VERSION 5.7 ;
BUSBITCHARS "[]" ;
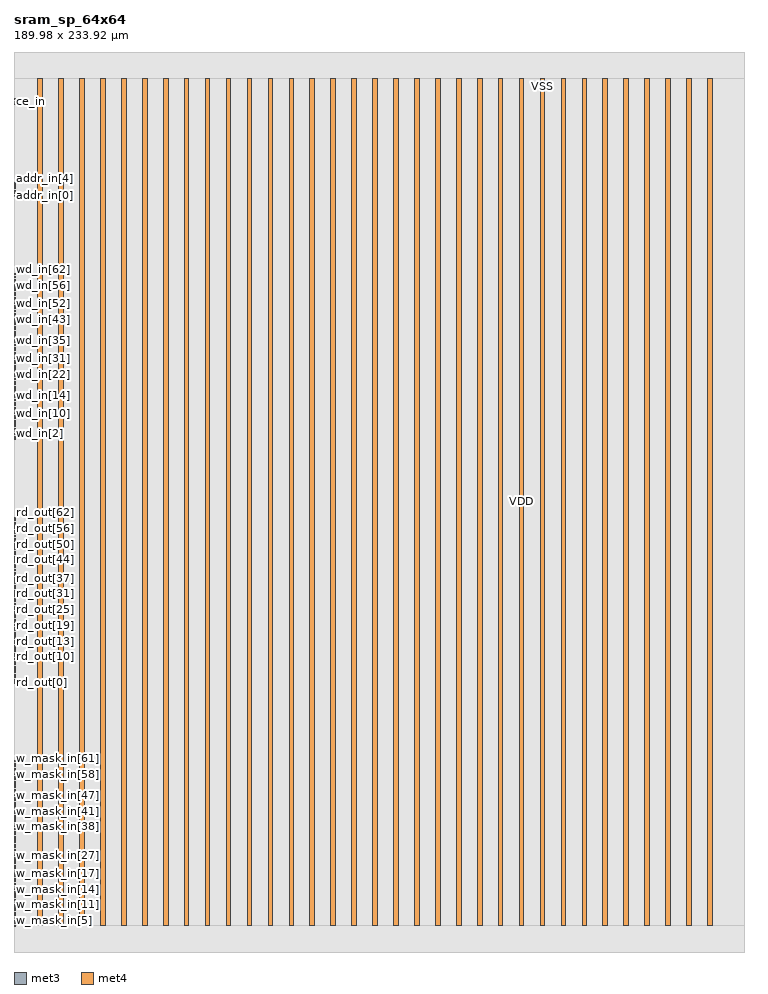
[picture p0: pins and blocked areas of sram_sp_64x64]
MACRO sram_sp_64x64
  FOREIGN sram_sp_64x64 0 0 ;
  SYMMETRY X Y R90 ;
  SIZE 189.980 BY 233.920 ;
  CLASS BLOCK ;
  PIN w_mask_in[0]
    DIRECTION INPUT ;
    USE SIGNAL ;
    SHAPE ABUTMENT ;
    PORT
      LAYER met3 ;
      RECT 0.000 6.650 0.300 6.950 ;
    END
  END w_mask_in[0]
  PIN w_mask_in[1]
    DIRECTION INPUT ;
    USE SIGNAL ;
    SHAPE ABUTMENT ;
    PORT
      LAYER met3 ;
      RECT 0.000 7.330 0.300 7.630 ;
    END
  END w_mask_in[1]
  PIN w_mask_in[2]
    DIRECTION INPUT ;
    USE SIGNAL ;
    SHAPE ABUTMENT ;
    PORT
      LAYER met3 ;
      RECT 0.000 8.010 0.300 8.310 ;
    END
  END w_mask_in[2]
  PIN w_mask_in[3]
    DIRECTION INPUT ;
    USE SIGNAL ;
    SHAPE ABUTMENT ;
    PORT
      LAYER met3 ;
      RECT 0.000 8.690 0.300 8.990 ;
    END
  END w_mask_in[3]
  PIN w_mask_in[4]
    DIRECTION INPUT ;
    USE SIGNAL ;
    SHAPE ABUTMENT ;
    PORT
      LAYER met3 ;
      RECT 0.000 9.370 0.300 9.670 ;
    END
  END w_mask_in[4]
  PIN w_mask_in[5]
    DIRECTION INPUT ;
    USE SIGNAL ;
    SHAPE ABUTMENT ;
    PORT
      LAYER met3 ;
      RECT 0.000 10.050 0.300 10.350 ;
    END
  END w_mask_in[5]
  PIN w_mask_in[6]
    DIRECTION INPUT ;
    USE SIGNAL ;
    SHAPE ABUTMENT ;
    PORT
      LAYER met3 ;
      RECT 0.000 10.730 0.300 11.030 ;
    END
  END w_mask_in[6]
  PIN w_mask_in[7]
    DIRECTION INPUT ;
    USE SIGNAL ;
    SHAPE ABUTMENT ;
    PORT
      LAYER met3 ;
      RECT 0.000 11.410 0.300 11.710 ;
    END
  END w_mask_in[7]
  PIN w_mask_in[8]
    DIRECTION INPUT ;
    USE SIGNAL ;
    SHAPE ABUTMENT ;
    PORT
      LAYER met3 ;
      RECT 0.000 12.090 0.300 12.390 ;
    END
  END w_mask_in[8]
  PIN w_mask_in[9]
    DIRECTION INPUT ;
    USE SIGNAL ;
    SHAPE ABUTMENT ;
    PORT
      LAYER met3 ;
      RECT 0.000 12.770 0.300 13.070 ;
    END
  END w_mask_in[9]
  PIN w_mask_in[10]
    DIRECTION INPUT ;
    USE SIGNAL ;
    SHAPE ABUTMENT ;
    PORT
      LAYER met3 ;
      RECT 0.000 13.450 0.300 13.750 ;
    END
  END w_mask_in[10]
  PIN w_mask_in[11]
    DIRECTION INPUT ;
    USE SIGNAL ;
    SHAPE ABUTMENT ;
    PORT
      LAYER met3 ;
      RECT 0.000 14.130 0.300 14.430 ;
    END
  END w_mask_in[11]
  PIN w_mask_in[12]
    DIRECTION INPUT ;
    USE SIGNAL ;
    SHAPE ABUTMENT ;
    PORT
      LAYER met3 ;
      RECT 0.000 14.810 0.300 15.110 ;
    END
  END w_mask_in[12]
  PIN w_mask_in[13]
    DIRECTION INPUT ;
    USE SIGNAL ;
    SHAPE ABUTMENT ;
    PORT
      LAYER met3 ;
      RECT 0.000 15.490 0.300 15.790 ;
    END
  END w_mask_in[13]
  PIN w_mask_in[14]
    DIRECTION INPUT ;
    USE SIGNAL ;
    SHAPE ABUTMENT ;
    PORT
      LAYER met3 ;
      RECT 0.000 16.170 0.300 16.470 ;
    END
  END w_mask_in[14]
  PIN w_mask_in[15]
    DIRECTION INPUT ;
    USE SIGNAL ;
    SHAPE ABUTMENT ;
    PORT
      LAYER met3 ;
      RECT 0.000 16.850 0.300 17.150 ;
    END
  END w_mask_in[15]
  PIN w_mask_in[16]
    DIRECTION INPUT ;
    USE SIGNAL ;
    SHAPE ABUTMENT ;
    PORT
      LAYER met3 ;
      RECT 0.000 17.530 0.300 17.830 ;
    END
  END w_mask_in[16]
  PIN w_mask_in[17]
    DIRECTION INPUT ;
    USE SIGNAL ;
    SHAPE ABUTMENT ;
    PORT
      LAYER met3 ;
      RECT 0.000 18.210 0.300 18.510 ;
    END
  END w_mask_in[17]
  PIN w_mask_in[18]
    DIRECTION INPUT ;
    USE SIGNAL ;
    SHAPE ABUTMENT ;
    PORT
      LAYER met3 ;
      RECT 0.000 18.890 0.300 19.190 ;
    END
  END w_mask_in[18]
  PIN w_mask_in[19]
    DIRECTION INPUT ;
    USE SIGNAL ;
    SHAPE ABUTMENT ;
    PORT
      LAYER met3 ;
      RECT 0.000 19.570 0.300 19.870 ;
    END
  END w_mask_in[19]
  PIN w_mask_in[20]
    DIRECTION INPUT ;
    USE SIGNAL ;
    SHAPE ABUTMENT ;
    PORT
      LAYER met3 ;
      RECT 0.000 20.250 0.300 20.550 ;
    END
  END w_mask_in[20]
  PIN w_mask_in[21]
    DIRECTION INPUT ;
    USE SIGNAL ;
    SHAPE ABUTMENT ;
    PORT
      LAYER met3 ;
      RECT 0.000 20.930 0.300 21.230 ;
    END
  END w_mask_in[21]
  PIN w_mask_in[22]
    DIRECTION INPUT ;
    USE SIGNAL ;
    SHAPE ABUTMENT ;
    PORT
      LAYER met3 ;
      RECT 0.000 21.610 0.300 21.910 ;
    END
  END w_mask_in[22]
  PIN w_mask_in[23]
    DIRECTION INPUT ;
    USE SIGNAL ;
    SHAPE ABUTMENT ;
    PORT
      LAYER met3 ;
      RECT 0.000 22.290 0.300 22.590 ;
    END
  END w_mask_in[23]
  PIN w_mask_in[24]
    DIRECTION INPUT ;
    USE SIGNAL ;
    SHAPE ABUTMENT ;
    PORT
      LAYER met3 ;
      RECT 0.000 22.970 0.300 23.270 ;
    END
  END w_mask_in[24]
  PIN w_mask_in[25]
    DIRECTION INPUT ;
    USE SIGNAL ;
    SHAPE ABUTMENT ;
    PORT
      LAYER met3 ;
      RECT 0.000 23.650 0.300 23.950 ;
    END
  END w_mask_in[25]
  PIN w_mask_in[26]
    DIRECTION INPUT ;
    USE SIGNAL ;
    SHAPE ABUTMENT ;
    PORT
      LAYER met3 ;
      RECT 0.000 24.330 0.300 24.630 ;
    END
  END w_mask_in[26]
  PIN w_mask_in[27]
    DIRECTION INPUT ;
    USE SIGNAL ;
    SHAPE ABUTMENT ;
    PORT
      LAYER met3 ;
      RECT 0.000 25.010 0.300 25.310 ;
    END
  END w_mask_in[27]
  PIN w_mask_in[28]
    DIRECTION INPUT ;
    USE SIGNAL ;
    SHAPE ABUTMENT ;
    PORT
      LAYER met3 ;
      RECT 0.000 25.690 0.300 25.990 ;
    END
  END w_mask_in[28]
  PIN w_mask_in[29]
    DIRECTION INPUT ;
    USE SIGNAL ;
    SHAPE ABUTMENT ;
    PORT
      LAYER met3 ;
      RECT 0.000 26.370 0.300 26.670 ;
    END
  END w_mask_in[29]
  PIN w_mask_in[30]
    DIRECTION INPUT ;
    USE SIGNAL ;
    SHAPE ABUTMENT ;
    PORT
      LAYER met3 ;
      RECT 0.000 27.050 0.300 27.350 ;
    END
  END w_mask_in[30]
  PIN w_mask_in[31]
    DIRECTION INPUT ;
    USE SIGNAL ;
    SHAPE ABUTMENT ;
    PORT
      LAYER met3 ;
      RECT 0.000 27.730 0.300 28.030 ;
    END
  END w_mask_in[31]
  PIN w_mask_in[32]
    DIRECTION INPUT ;
    USE SIGNAL ;
    SHAPE ABUTMENT ;
    PORT
      LAYER met3 ;
      RECT 0.000 28.410 0.300 28.710 ;
    END
  END w_mask_in[32]
  PIN w_mask_in[33]
    DIRECTION INPUT ;
    USE SIGNAL ;
    SHAPE ABUTMENT ;
    PORT
      LAYER met3 ;
      RECT 0.000 29.090 0.300 29.390 ;
    END
  END w_mask_in[33]
  PIN w_mask_in[34]
    DIRECTION INPUT ;
    USE SIGNAL ;
    SHAPE ABUTMENT ;
    PORT
      LAYER met3 ;
      RECT 0.000 29.770 0.300 30.070 ;
    END
  END w_mask_in[34]
  PIN w_mask_in[35]
    DIRECTION INPUT ;
    USE SIGNAL ;
    SHAPE ABUTMENT ;
    PORT
      LAYER met3 ;
      RECT 0.000 30.450 0.300 30.750 ;
    END
  END w_mask_in[35]
  PIN w_mask_in[36]
    DIRECTION INPUT ;
    USE SIGNAL ;
    SHAPE ABUTMENT ;
    PORT
      LAYER met3 ;
      RECT 0.000 31.130 0.300 31.430 ;
    END
  END w_mask_in[36]
  PIN w_mask_in[37]
    DIRECTION INPUT ;
    USE SIGNAL ;
    SHAPE ABUTMENT ;
    PORT
      LAYER met3 ;
      RECT 0.000 31.810 0.300 32.110 ;
    END
  END w_mask_in[37]
  PIN w_mask_in[38]
    DIRECTION INPUT ;
    USE SIGNAL ;
    SHAPE ABUTMENT ;
    PORT
      LAYER met3 ;
      RECT 0.000 32.490 0.300 32.790 ;
    END
  END w_mask_in[38]
  PIN w_mask_in[39]
    DIRECTION INPUT ;
    USE SIGNAL ;
    SHAPE ABUTMENT ;
    PORT
      LAYER met3 ;
      RECT 0.000 33.170 0.300 33.470 ;
    END
  END w_mask_in[39]
  PIN w_mask_in[40]
    DIRECTION INPUT ;
    USE SIGNAL ;
    SHAPE ABUTMENT ;
    PORT
      LAYER met3 ;
      RECT 0.000 33.850 0.300 34.150 ;
    END
  END w_mask_in[40]
  PIN w_mask_in[41]
    DIRECTION INPUT ;
    USE SIGNAL ;
    SHAPE ABUTMENT ;
    PORT
      LAYER met3 ;
      RECT 0.000 34.530 0.300 34.830 ;
    END
  END w_mask_in[41]
  PIN w_mask_in[42]
    DIRECTION INPUT ;
    USE SIGNAL ;
    SHAPE ABUTMENT ;
    PORT
      LAYER met3 ;
      RECT 0.000 35.210 0.300 35.510 ;
    END
  END w_mask_in[42]
  PIN w_mask_in[43]
    DIRECTION INPUT ;
    USE SIGNAL ;
    SHAPE ABUTMENT ;
    PORT
      LAYER met3 ;
      RECT 0.000 35.890 0.300 36.190 ;
    END
  END w_mask_in[43]
  PIN w_mask_in[44]
    DIRECTION INPUT ;
    USE SIGNAL ;
    SHAPE ABUTMENT ;
    PORT
      LAYER met3 ;
      RECT 0.000 36.570 0.300 36.870 ;
    END
  END w_mask_in[44]
  PIN w_mask_in[45]
    DIRECTION INPUT ;
    USE SIGNAL ;
    SHAPE ABUTMENT ;
    PORT
      LAYER met3 ;
      RECT 0.000 37.250 0.300 37.550 ;
    END
  END w_mask_in[45]
  PIN w_mask_in[46]
    DIRECTION INPUT ;
    USE SIGNAL ;
    SHAPE ABUTMENT ;
    PORT
      LAYER met3 ;
      RECT 0.000 37.930 0.300 38.230 ;
    END
  END w_mask_in[46]
  PIN w_mask_in[47]
    DIRECTION INPUT ;
    USE SIGNAL ;
    SHAPE ABUTMENT ;
    PORT
      LAYER met3 ;
      RECT 0.000 38.610 0.300 38.910 ;
    END
  END w_mask_in[47]
  PIN w_mask_in[48]
    DIRECTION INPUT ;
    USE SIGNAL ;
    SHAPE ABUTMENT ;
    PORT
      LAYER met3 ;
      RECT 0.000 39.290 0.300 39.590 ;
    END
  END w_mask_in[48]
  PIN w_mask_in[49]
    DIRECTION INPUT ;
    USE SIGNAL ;
    SHAPE ABUTMENT ;
    PORT
      LAYER met3 ;
      RECT 0.000 39.970 0.300 40.270 ;
    END
  END w_mask_in[49]
  PIN w_mask_in[50]
    DIRECTION INPUT ;
    USE SIGNAL ;
    SHAPE ABUTMENT ;
    PORT
      LAYER met3 ;
      RECT 0.000 40.650 0.300 40.950 ;
    END
  END w_mask_in[50]
  PIN w_mask_in[51]
    DIRECTION INPUT ;
    USE SIGNAL ;
    SHAPE ABUTMENT ;
    PORT
      LAYER met3 ;
      RECT 0.000 41.330 0.300 41.630 ;
    END
  END w_mask_in[51]
  PIN w_mask_in[52]
    DIRECTION INPUT ;
    USE SIGNAL ;
    SHAPE ABUTMENT ;
    PORT
      LAYER met3 ;
      RECT 0.000 42.010 0.300 42.310 ;
    END
  END w_mask_in[52]
  PIN w_mask_in[53]
    DIRECTION INPUT ;
    USE SIGNAL ;
    SHAPE ABUTMENT ;
    PORT
      LAYER met3 ;
      RECT 0.000 42.690 0.300 42.990 ;
    END
  END w_mask_in[53]
  PIN w_mask_in[54]
    DIRECTION INPUT ;
    USE SIGNAL ;
    SHAPE ABUTMENT ;
    PORT
      LAYER met3 ;
      RECT 0.000 43.370 0.300 43.670 ;
    END
  END w_mask_in[54]
  PIN w_mask_in[55]
    DIRECTION INPUT ;
    USE SIGNAL ;
    SHAPE ABUTMENT ;
    PORT
      LAYER met3 ;
      RECT 0.000 44.050 0.300 44.350 ;
    END
  END w_mask_in[55]
  PIN w_mask_in[56]
    DIRECTION INPUT ;
    USE SIGNAL ;
    SHAPE ABUTMENT ;
    PORT
      LAYER met3 ;
      RECT 0.000 44.730 0.300 45.030 ;
    END
  END w_mask_in[56]
  PIN w_mask_in[57]
    DIRECTION INPUT ;
    USE SIGNAL ;
    SHAPE ABUTMENT ;
    PORT
      LAYER met3 ;
      RECT 0.000 45.410 0.300 45.710 ;
    END
  END w_mask_in[57]
  PIN w_mask_in[58]
    DIRECTION INPUT ;
    USE SIGNAL ;
    SHAPE ABUTMENT ;
    PORT
      LAYER met3 ;
      RECT 0.000 46.090 0.300 46.390 ;
    END
  END w_mask_in[58]
  PIN w_mask_in[59]
    DIRECTION INPUT ;
    USE SIGNAL ;
    SHAPE ABUTMENT ;
    PORT
      LAYER met3 ;
      RECT 0.000 46.770 0.300 47.070 ;
    END
  END w_mask_in[59]
  PIN w_mask_in[60]
    DIRECTION INPUT ;
    USE SIGNAL ;
    SHAPE ABUTMENT ;
    PORT
      LAYER met3 ;
      RECT 0.000 47.450 0.300 47.750 ;
    END
  END w_mask_in[60]
  PIN w_mask_in[61]
    DIRECTION INPUT ;
    USE SIGNAL ;
    SHAPE ABUTMENT ;
    PORT
      LAYER met3 ;
      RECT 0.000 48.130 0.300 48.430 ;
    END
  END w_mask_in[61]
  PIN w_mask_in[62]
    DIRECTION INPUT ;
    USE SIGNAL ;
    SHAPE ABUTMENT ;
    PORT
      LAYER met3 ;
      RECT 0.000 48.810 0.300 49.110 ;
    END
  END w_mask_in[62]
  PIN w_mask_in[63]
    DIRECTION INPUT ;
    USE SIGNAL ;
    SHAPE ABUTMENT ;
    PORT
      LAYER met3 ;
      RECT 0.000 49.490 0.300 49.790 ;
    END
  END w_mask_in[63]
  PIN rd_out[0]
    DIRECTION OUTPUT ;
    USE SIGNAL ;
    SHAPE ABUTMENT ;
    PORT
      LAYER met3 ;
      RECT 0.000 69.890 0.300 70.190 ;
    END
  END rd_out[0]
  PIN rd_out[1]
    DIRECTION OUTPUT ;
    USE SIGNAL ;
    SHAPE ABUTMENT ;
    PORT
      LAYER met3 ;
      RECT 0.000 70.570 0.300 70.870 ;
    END
  END rd_out[1]
  PIN rd_out[2]
    DIRECTION OUTPUT ;
    USE SIGNAL ;
    SHAPE ABUTMENT ;
    PORT
      LAYER met3 ;
      RECT 0.000 71.250 0.300 71.550 ;
    END
  END rd_out[2]
  PIN rd_out[3]
    DIRECTION OUTPUT ;
    USE SIGNAL ;
    SHAPE ABUTMENT ;
    PORT
      LAYER met3 ;
      RECT 0.000 71.930 0.300 72.230 ;
    END
  END rd_out[3]
  PIN rd_out[4]
    DIRECTION OUTPUT ;
    USE SIGNAL ;
    SHAPE ABUTMENT ;
    PORT
      LAYER met3 ;
      RECT 0.000 72.610 0.300 72.910 ;
    END
  END rd_out[4]
  PIN rd_out[5]
    DIRECTION OUTPUT ;
    USE SIGNAL ;
    SHAPE ABUTMENT ;
    PORT
      LAYER met3 ;
      RECT 0.000 73.290 0.300 73.590 ;
    END
  END rd_out[5]
  PIN rd_out[6]
    DIRECTION OUTPUT ;
    USE SIGNAL ;
    SHAPE ABUTMENT ;
    PORT
      LAYER met3 ;
      RECT 0.000 73.970 0.300 74.270 ;
    END
  END rd_out[6]
  PIN rd_out[7]
    DIRECTION OUTPUT ;
    USE SIGNAL ;
    SHAPE ABUTMENT ;
    PORT
      LAYER met3 ;
      RECT 0.000 74.650 0.300 74.950 ;
    END
  END rd_out[7]
  PIN rd_out[8]
    DIRECTION OUTPUT ;
    USE SIGNAL ;
    SHAPE ABUTMENT ;
    PORT
      LAYER met3 ;
      RECT 0.000 75.330 0.300 75.630 ;
    END
  END rd_out[8]
  PIN rd_out[9]
    DIRECTION OUTPUT ;
    USE SIGNAL ;
    SHAPE ABUTMENT ;
    PORT
      LAYER met3 ;
      RECT 0.000 76.010 0.300 76.310 ;
    END
  END rd_out[9]
  PIN rd_out[10]
    DIRECTION OUTPUT ;
    USE SIGNAL ;
    SHAPE ABUTMENT ;
    PORT
      LAYER met3 ;
      RECT 0.000 76.690 0.300 76.990 ;
    END
  END rd_out[10]
  PIN rd_out[11]
    DIRECTION OUTPUT ;
    USE SIGNAL ;
    SHAPE ABUTMENT ;
    PORT
      LAYER met3 ;
      RECT 0.000 77.370 0.300 77.670 ;
    END
  END rd_out[11]
  PIN rd_out[12]
    DIRECTION OUTPUT ;
    USE SIGNAL ;
    SHAPE ABUTMENT ;
    PORT
      LAYER met3 ;
      RECT 0.000 78.050 0.300 78.350 ;
    END
  END rd_out[12]
  PIN rd_out[13]
    DIRECTION OUTPUT ;
    USE SIGNAL ;
    SHAPE ABUTMENT ;
    PORT
      LAYER met3 ;
      RECT 0.000 78.730 0.300 79.030 ;
    END
  END rd_out[13]
  PIN rd_out[14]
    DIRECTION OUTPUT ;
    USE SIGNAL ;
    SHAPE ABUTMENT ;
    PORT
      LAYER met3 ;
      RECT 0.000 79.410 0.300 79.710 ;
    END
  END rd_out[14]
  PIN rd_out[15]
    DIRECTION OUTPUT ;
    USE SIGNAL ;
    SHAPE ABUTMENT ;
    PORT
      LAYER met3 ;
      RECT 0.000 80.090 0.300 80.390 ;
    END
  END rd_out[15]
  PIN rd_out[16]
    DIRECTION OUTPUT ;
    USE SIGNAL ;
    SHAPE ABUTMENT ;
    PORT
      LAYER met3 ;
      RECT 0.000 80.770 0.300 81.070 ;
    END
  END rd_out[16]
  PIN rd_out[17]
    DIRECTION OUTPUT ;
    USE SIGNAL ;
    SHAPE ABUTMENT ;
    PORT
      LAYER met3 ;
      RECT 0.000 81.450 0.300 81.750 ;
    END
  END rd_out[17]
  PIN rd_out[18]
    DIRECTION OUTPUT ;
    USE SIGNAL ;
    SHAPE ABUTMENT ;
    PORT
      LAYER met3 ;
      RECT 0.000 82.130 0.300 82.430 ;
    END
  END rd_out[18]
  PIN rd_out[19]
    DIRECTION OUTPUT ;
    USE SIGNAL ;
    SHAPE ABUTMENT ;
    PORT
      LAYER met3 ;
      RECT 0.000 82.810 0.300 83.110 ;
    END
  END rd_out[19]
  PIN rd_out[20]
    DIRECTION OUTPUT ;
    USE SIGNAL ;
    SHAPE ABUTMENT ;
    PORT
      LAYER met3 ;
      RECT 0.000 83.490 0.300 83.790 ;
    END
  END rd_out[20]
  PIN rd_out[21]
    DIRECTION OUTPUT ;
    USE SIGNAL ;
    SHAPE ABUTMENT ;
    PORT
      LAYER met3 ;
      RECT 0.000 84.170 0.300 84.470 ;
    END
  END rd_out[21]
  PIN rd_out[22]
    DIRECTION OUTPUT ;
    USE SIGNAL ;
    SHAPE ABUTMENT ;
    PORT
      LAYER met3 ;
      RECT 0.000 84.850 0.300 85.150 ;
    END
  END rd_out[22]
  PIN rd_out[23]
    DIRECTION OUTPUT ;
    USE SIGNAL ;
    SHAPE ABUTMENT ;
    PORT
      LAYER met3 ;
      RECT 0.000 85.530 0.300 85.830 ;
    END
  END rd_out[23]
  PIN rd_out[24]
    DIRECTION OUTPUT ;
    USE SIGNAL ;
    SHAPE ABUTMENT ;
    PORT
      LAYER met3 ;
      RECT 0.000 86.210 0.300 86.510 ;
    END
  END rd_out[24]
  PIN rd_out[25]
    DIRECTION OUTPUT ;
    USE SIGNAL ;
    SHAPE ABUTMENT ;
    PORT
      LAYER met3 ;
      RECT 0.000 86.890 0.300 87.190 ;
    END
  END rd_out[25]
  PIN rd_out[26]
    DIRECTION OUTPUT ;
    USE SIGNAL ;
    SHAPE ABUTMENT ;
    PORT
      LAYER met3 ;
      RECT 0.000 87.570 0.300 87.870 ;
    END
  END rd_out[26]
  PIN rd_out[27]
    DIRECTION OUTPUT ;
    USE SIGNAL ;
    SHAPE ABUTMENT ;
    PORT
      LAYER met3 ;
      RECT 0.000 88.250 0.300 88.550 ;
    END
  END rd_out[27]
  PIN rd_out[28]
    DIRECTION OUTPUT ;
    USE SIGNAL ;
    SHAPE ABUTMENT ;
    PORT
      LAYER met3 ;
      RECT 0.000 88.930 0.300 89.230 ;
    END
  END rd_out[28]
  PIN rd_out[29]
    DIRECTION OUTPUT ;
    USE SIGNAL ;
    SHAPE ABUTMENT ;
    PORT
      LAYER met3 ;
      RECT 0.000 89.610 0.300 89.910 ;
    END
  END rd_out[29]
  PIN rd_out[30]
    DIRECTION OUTPUT ;
    USE SIGNAL ;
    SHAPE ABUTMENT ;
    PORT
      LAYER met3 ;
      RECT 0.000 90.290 0.300 90.590 ;
    END
  END rd_out[30]
  PIN rd_out[31]
    DIRECTION OUTPUT ;
    USE SIGNAL ;
    SHAPE ABUTMENT ;
    PORT
      LAYER met3 ;
      RECT 0.000 90.970 0.300 91.270 ;
    END
  END rd_out[31]
  PIN rd_out[32]
    DIRECTION OUTPUT ;
    USE SIGNAL ;
    SHAPE ABUTMENT ;
    PORT
      LAYER met3 ;
      RECT 0.000 91.650 0.300 91.950 ;
    END
  END rd_out[32]
  PIN rd_out[33]
    DIRECTION OUTPUT ;
    USE SIGNAL ;
    SHAPE ABUTMENT ;
    PORT
      LAYER met3 ;
      RECT 0.000 92.330 0.300 92.630 ;
    END
  END rd_out[33]
  PIN rd_out[34]
    DIRECTION OUTPUT ;
    USE SIGNAL ;
    SHAPE ABUTMENT ;
    PORT
      LAYER met3 ;
      RECT 0.000 93.010 0.300 93.310 ;
    END
  END rd_out[34]
  PIN rd_out[35]
    DIRECTION OUTPUT ;
    USE SIGNAL ;
    SHAPE ABUTMENT ;
    PORT
      LAYER met3 ;
      RECT 0.000 93.690 0.300 93.990 ;
    END
  END rd_out[35]
  PIN rd_out[36]
    DIRECTION OUTPUT ;
    USE SIGNAL ;
    SHAPE ABUTMENT ;
    PORT
      LAYER met3 ;
      RECT 0.000 94.370 0.300 94.670 ;
    END
  END rd_out[36]
  PIN rd_out[37]
    DIRECTION OUTPUT ;
    USE SIGNAL ;
    SHAPE ABUTMENT ;
    PORT
      LAYER met3 ;
      RECT 0.000 95.050 0.300 95.350 ;
    END
  END rd_out[37]
  PIN rd_out[38]
    DIRECTION OUTPUT ;
    USE SIGNAL ;
    SHAPE ABUTMENT ;
    PORT
      LAYER met3 ;
      RECT 0.000 95.730 0.300 96.030 ;
    END
  END rd_out[38]
  PIN rd_out[39]
    DIRECTION OUTPUT ;
    USE SIGNAL ;
    SHAPE ABUTMENT ;
    PORT
      LAYER met3 ;
      RECT 0.000 96.410 0.300 96.710 ;
    END
  END rd_out[39]
  PIN rd_out[40]
    DIRECTION OUTPUT ;
    USE SIGNAL ;
    SHAPE ABUTMENT ;
    PORT
      LAYER met3 ;
      RECT 0.000 97.090 0.300 97.390 ;
    END
  END rd_out[40]
  PIN rd_out[41]
    DIRECTION OUTPUT ;
    USE SIGNAL ;
    SHAPE ABUTMENT ;
    PORT
      LAYER met3 ;
      RECT 0.000 97.770 0.300 98.070 ;
    END
  END rd_out[41]
  PIN rd_out[42]
    DIRECTION OUTPUT ;
    USE SIGNAL ;
    SHAPE ABUTMENT ;
    PORT
      LAYER met3 ;
      RECT 0.000 98.450 0.300 98.750 ;
    END
  END rd_out[42]
  PIN rd_out[43]
    DIRECTION OUTPUT ;
    USE SIGNAL ;
    SHAPE ABUTMENT ;
    PORT
      LAYER met3 ;
      RECT 0.000 99.130 0.300 99.430 ;
    END
  END rd_out[43]
  PIN rd_out[44]
    DIRECTION OUTPUT ;
    USE SIGNAL ;
    SHAPE ABUTMENT ;
    PORT
      LAYER met3 ;
      RECT 0.000 99.810 0.300 100.110 ;
    END
  END rd_out[44]
  PIN rd_out[45]
    DIRECTION OUTPUT ;
    USE SIGNAL ;
    SHAPE ABUTMENT ;
    PORT
      LAYER met3 ;
      RECT 0.000 100.490 0.300 100.790 ;
    END
  END rd_out[45]
  PIN rd_out[46]
    DIRECTION OUTPUT ;
    USE SIGNAL ;
    SHAPE ABUTMENT ;
    PORT
      LAYER met3 ;
      RECT 0.000 101.170 0.300 101.470 ;
    END
  END rd_out[46]
  PIN rd_out[47]
    DIRECTION OUTPUT ;
    USE SIGNAL ;
    SHAPE ABUTMENT ;
    PORT
      LAYER met3 ;
      RECT 0.000 101.850 0.300 102.150 ;
    END
  END rd_out[47]
  PIN rd_out[48]
    DIRECTION OUTPUT ;
    USE SIGNAL ;
    SHAPE ABUTMENT ;
    PORT
      LAYER met3 ;
      RECT 0.000 102.530 0.300 102.830 ;
    END
  END rd_out[48]
  PIN rd_out[49]
    DIRECTION OUTPUT ;
    USE SIGNAL ;
    SHAPE ABUTMENT ;
    PORT
      LAYER met3 ;
      RECT 0.000 103.210 0.300 103.510 ;
    END
  END rd_out[49]
  PIN rd_out[50]
    DIRECTION OUTPUT ;
    USE SIGNAL ;
    SHAPE ABUTMENT ;
    PORT
      LAYER met3 ;
      RECT 0.000 103.890 0.300 104.190 ;
    END
  END rd_out[50]
  PIN rd_out[51]
    DIRECTION OUTPUT ;
    USE SIGNAL ;
    SHAPE ABUTMENT ;
    PORT
      LAYER met3 ;
      RECT 0.000 104.570 0.300 104.870 ;
    END
  END rd_out[51]
  PIN rd_out[52]
    DIRECTION OUTPUT ;
    USE SIGNAL ;
    SHAPE ABUTMENT ;
    PORT
      LAYER met3 ;
      RECT 0.000 105.250 0.300 105.550 ;
    END
  END rd_out[52]
  PIN rd_out[53]
    DIRECTION OUTPUT ;
    USE SIGNAL ;
    SHAPE ABUTMENT ;
    PORT
      LAYER met3 ;
      RECT 0.000 105.930 0.300 106.230 ;
    END
  END rd_out[53]
  PIN rd_out[54]
    DIRECTION OUTPUT ;
    USE SIGNAL ;
    SHAPE ABUTMENT ;
    PORT
      LAYER met3 ;
      RECT 0.000 106.610 0.300 106.910 ;
    END
  END rd_out[54]
  PIN rd_out[55]
    DIRECTION OUTPUT ;
    USE SIGNAL ;
    SHAPE ABUTMENT ;
    PORT
      LAYER met3 ;
      RECT 0.000 107.290 0.300 107.590 ;
    END
  END rd_out[55]
  PIN rd_out[56]
    DIRECTION OUTPUT ;
    USE SIGNAL ;
    SHAPE ABUTMENT ;
    PORT
      LAYER met3 ;
      RECT 0.000 107.970 0.300 108.270 ;
    END
  END rd_out[56]
  PIN rd_out[57]
    DIRECTION OUTPUT ;
    USE SIGNAL ;
    SHAPE ABUTMENT ;
    PORT
      LAYER met3 ;
      RECT 0.000 108.650 0.300 108.950 ;
    END
  END rd_out[57]
  PIN rd_out[58]
    DIRECTION OUTPUT ;
    USE SIGNAL ;
    SHAPE ABUTMENT ;
    PORT
      LAYER met3 ;
      RECT 0.000 109.330 0.300 109.630 ;
    END
  END rd_out[58]
  PIN rd_out[59]
    DIRECTION OUTPUT ;
    USE SIGNAL ;
    SHAPE ABUTMENT ;
    PORT
      LAYER met3 ;
      RECT 0.000 110.010 0.300 110.310 ;
    END
  END rd_out[59]
  PIN rd_out[60]
    DIRECTION OUTPUT ;
    USE SIGNAL ;
    SHAPE ABUTMENT ;
    PORT
      LAYER met3 ;
      RECT 0.000 110.690 0.300 110.990 ;
    END
  END rd_out[60]
  PIN rd_out[61]
    DIRECTION OUTPUT ;
    USE SIGNAL ;
    SHAPE ABUTMENT ;
    PORT
      LAYER met3 ;
      RECT 0.000 111.370 0.300 111.670 ;
    END
  END rd_out[61]
  PIN rd_out[62]
    DIRECTION OUTPUT ;
    USE SIGNAL ;
    SHAPE ABUTMENT ;
    PORT
      LAYER met3 ;
      RECT 0.000 112.050 0.300 112.350 ;
    END
  END rd_out[62]
  PIN rd_out[63]
    DIRECTION OUTPUT ;
    USE SIGNAL ;
    SHAPE ABUTMENT ;
    PORT
      LAYER met3 ;
      RECT 0.000 112.730 0.300 113.030 ;
    END
  END rd_out[63]
  PIN wd_in[0]
    DIRECTION INPUT ;
    USE SIGNAL ;
    SHAPE ABUTMENT ;
    PORT
      LAYER met3 ;
      RECT 0.000 133.130 0.300 133.430 ;
    END
  END wd_in[0]
  PIN wd_in[1]
    DIRECTION INPUT ;
    USE SIGNAL ;
    SHAPE ABUTMENT ;
    PORT
      LAYER met3 ;
      RECT 0.000 133.810 0.300 134.110 ;
    END
  END wd_in[1]
  PIN wd_in[2]
    DIRECTION INPUT ;
    USE SIGNAL ;
    SHAPE ABUTMENT ;
    PORT
      LAYER met3 ;
      RECT 0.000 134.490 0.300 134.790 ;
    END
  END wd_in[2]
  PIN wd_in[3]
    DIRECTION INPUT ;
    USE SIGNAL ;
    SHAPE ABUTMENT ;
    PORT
      LAYER met3 ;
      RECT 0.000 135.170 0.300 135.470 ;
    END
  END wd_in[3]
  PIN wd_in[4]
    DIRECTION INPUT ;
    USE SIGNAL ;
    SHAPE ABUTMENT ;
    PORT
      LAYER met3 ;
      RECT 0.000 135.850 0.300 136.150 ;
    END
  END wd_in[4]
  PIN wd_in[5]
    DIRECTION INPUT ;
    USE SIGNAL ;
    SHAPE ABUTMENT ;
    PORT
      LAYER met3 ;
      RECT 0.000 136.530 0.300 136.830 ;
    END
  END wd_in[5]
  PIN wd_in[6]
    DIRECTION INPUT ;
    USE SIGNAL ;
    SHAPE ABUTMENT ;
    PORT
      LAYER met3 ;
      RECT 0.000 137.210 0.300 137.510 ;
    END
  END wd_in[6]
  PIN wd_in[7]
    DIRECTION INPUT ;
    USE SIGNAL ;
    SHAPE ABUTMENT ;
    PORT
      LAYER met3 ;
      RECT 0.000 137.890 0.300 138.190 ;
    END
  END wd_in[7]
  PIN wd_in[8]
    DIRECTION INPUT ;
    USE SIGNAL ;
    SHAPE ABUTMENT ;
    PORT
      LAYER met3 ;
      RECT 0.000 138.570 0.300 138.870 ;
    END
  END wd_in[8]
  PIN wd_in[9]
    DIRECTION INPUT ;
    USE SIGNAL ;
    SHAPE ABUTMENT ;
    PORT
      LAYER met3 ;
      RECT 0.000 139.250 0.300 139.550 ;
    END
  END wd_in[9]
  PIN wd_in[10]
    DIRECTION INPUT ;
    USE SIGNAL ;
    SHAPE ABUTMENT ;
    PORT
      LAYER met3 ;
      RECT 0.000 139.930 0.300 140.230 ;
    END
  END wd_in[10]
  PIN wd_in[11]
    DIRECTION INPUT ;
    USE SIGNAL ;
    SHAPE ABUTMENT ;
    PORT
      LAYER met3 ;
      RECT 0.000 140.610 0.300 140.910 ;
    END
  END wd_in[11]
  PIN wd_in[12]
    DIRECTION INPUT ;
    USE SIGNAL ;
    SHAPE ABUTMENT ;
    PORT
      LAYER met3 ;
      RECT 0.000 141.290 0.300 141.590 ;
    END
  END wd_in[12]
  PIN wd_in[13]
    DIRECTION INPUT ;
    USE SIGNAL ;
    SHAPE ABUTMENT ;
    PORT
      LAYER met3 ;
      RECT 0.000 141.970 0.300 142.270 ;
    END
  END wd_in[13]
  PIN wd_in[14]
    DIRECTION INPUT ;
    USE SIGNAL ;
    SHAPE ABUTMENT ;
    PORT
      LAYER met3 ;
      RECT 0.000 142.650 0.300 142.950 ;
    END
  END wd_in[14]
  PIN wd_in[15]
    DIRECTION INPUT ;
    USE SIGNAL ;
    SHAPE ABUTMENT ;
    PORT
      LAYER met3 ;
      RECT 0.000 143.330 0.300 143.630 ;
    END
  END wd_in[15]
  PIN wd_in[16]
    DIRECTION INPUT ;
    USE SIGNAL ;
    SHAPE ABUTMENT ;
    PORT
      LAYER met3 ;
      RECT 0.000 144.010 0.300 144.310 ;
    END
  END wd_in[16]
  PIN wd_in[17]
    DIRECTION INPUT ;
    USE SIGNAL ;
    SHAPE ABUTMENT ;
    PORT
      LAYER met3 ;
      RECT 0.000 144.690 0.300 144.990 ;
    END
  END wd_in[17]
  PIN wd_in[18]
    DIRECTION INPUT ;
    USE SIGNAL ;
    SHAPE ABUTMENT ;
    PORT
      LAYER met3 ;
      RECT 0.000 145.370 0.300 145.670 ;
    END
  END wd_in[18]
  PIN wd_in[19]
    DIRECTION INPUT ;
    USE SIGNAL ;
    SHAPE ABUTMENT ;
    PORT
      LAYER met3 ;
      RECT 0.000 146.050 0.300 146.350 ;
    END
  END wd_in[19]
  PIN wd_in[20]
    DIRECTION INPUT ;
    USE SIGNAL ;
    SHAPE ABUTMENT ;
    PORT
      LAYER met3 ;
      RECT 0.000 146.730 0.300 147.030 ;
    END
  END wd_in[20]
  PIN wd_in[21]
    DIRECTION INPUT ;
    USE SIGNAL ;
    SHAPE ABUTMENT ;
    PORT
      LAYER met3 ;
      RECT 0.000 147.410 0.300 147.710 ;
    END
  END wd_in[21]
  PIN wd_in[22]
    DIRECTION INPUT ;
    USE SIGNAL ;
    SHAPE ABUTMENT ;
    PORT
      LAYER met3 ;
      RECT 0.000 148.090 0.300 148.390 ;
    END
  END wd_in[22]
  PIN wd_in[23]
    DIRECTION INPUT ;
    USE SIGNAL ;
    SHAPE ABUTMENT ;
    PORT
      LAYER met3 ;
      RECT 0.000 148.770 0.300 149.070 ;
    END
  END wd_in[23]
  PIN wd_in[24]
    DIRECTION INPUT ;
    USE SIGNAL ;
    SHAPE ABUTMENT ;
    PORT
      LAYER met3 ;
      RECT 0.000 149.450 0.300 149.750 ;
    END
  END wd_in[24]
  PIN wd_in[25]
    DIRECTION INPUT ;
    USE SIGNAL ;
    SHAPE ABUTMENT ;
    PORT
      LAYER met3 ;
      RECT 0.000 150.130 0.300 150.430 ;
    END
  END wd_in[25]
  PIN wd_in[26]
    DIRECTION INPUT ;
    USE SIGNAL ;
    SHAPE ABUTMENT ;
    PORT
      LAYER met3 ;
      RECT 0.000 150.810 0.300 151.110 ;
    END
  END wd_in[26]
  PIN wd_in[27]
    DIRECTION INPUT ;
    USE SIGNAL ;
    SHAPE ABUTMENT ;
    PORT
      LAYER met3 ;
      RECT 0.000 151.490 0.300 151.790 ;
    END
  END wd_in[27]
  PIN wd_in[28]
    DIRECTION INPUT ;
    USE SIGNAL ;
    SHAPE ABUTMENT ;
    PORT
      LAYER met3 ;
      RECT 0.000 152.170 0.300 152.470 ;
    END
  END wd_in[28]
  PIN wd_in[29]
    DIRECTION INPUT ;
    USE SIGNAL ;
    SHAPE ABUTMENT ;
    PORT
      LAYER met3 ;
      RECT 0.000 152.850 0.300 153.150 ;
    END
  END wd_in[29]
  PIN wd_in[30]
    DIRECTION INPUT ;
    USE SIGNAL ;
    SHAPE ABUTMENT ;
    PORT
      LAYER met3 ;
      RECT 0.000 153.530 0.300 153.830 ;
    END
  END wd_in[30]
  PIN wd_in[31]
    DIRECTION INPUT ;
    USE SIGNAL ;
    SHAPE ABUTMENT ;
    PORT
      LAYER met3 ;
      RECT 0.000 154.210 0.300 154.510 ;
    END
  END wd_in[31]
  PIN wd_in[32]
    DIRECTION INPUT ;
    USE SIGNAL ;
    SHAPE ABUTMENT ;
    PORT
      LAYER met3 ;
      RECT 0.000 154.890 0.300 155.190 ;
    END
  END wd_in[32]
  PIN wd_in[33]
    DIRECTION INPUT ;
    USE SIGNAL ;
    SHAPE ABUTMENT ;
    PORT
      LAYER met3 ;
      RECT 0.000 155.570 0.300 155.870 ;
    END
  END wd_in[33]
  PIN wd_in[34]
    DIRECTION INPUT ;
    USE SIGNAL ;
    SHAPE ABUTMENT ;
    PORT
      LAYER met3 ;
      RECT 0.000 156.250 0.300 156.550 ;
    END
  END wd_in[34]
  PIN wd_in[35]
    DIRECTION INPUT ;
    USE SIGNAL ;
    SHAPE ABUTMENT ;
    PORT
      LAYER met3 ;
      RECT 0.000 156.930 0.300 157.230 ;
    END
  END wd_in[35]
  PIN wd_in[36]
    DIRECTION INPUT ;
    USE SIGNAL ;
    SHAPE ABUTMENT ;
    PORT
      LAYER met3 ;
      RECT 0.000 157.610 0.300 157.910 ;
    END
  END wd_in[36]
  PIN wd_in[37]
    DIRECTION INPUT ;
    USE SIGNAL ;
    SHAPE ABUTMENT ;
    PORT
      LAYER met3 ;
      RECT 0.000 158.290 0.300 158.590 ;
    END
  END wd_in[37]
  PIN wd_in[38]
    DIRECTION INPUT ;
    USE SIGNAL ;
    SHAPE ABUTMENT ;
    PORT
      LAYER met3 ;
      RECT 0.000 158.970 0.300 159.270 ;
    END
  END wd_in[38]
  PIN wd_in[39]
    DIRECTION INPUT ;
    USE SIGNAL ;
    SHAPE ABUTMENT ;
    PORT
      LAYER met3 ;
      RECT 0.000 159.650 0.300 159.950 ;
    END
  END wd_in[39]
  PIN wd_in[40]
    DIRECTION INPUT ;
    USE SIGNAL ;
    SHAPE ABUTMENT ;
    PORT
      LAYER met3 ;
      RECT 0.000 160.330 0.300 160.630 ;
    END
  END wd_in[40]
  PIN wd_in[41]
    DIRECTION INPUT ;
    USE SIGNAL ;
    SHAPE ABUTMENT ;
    PORT
      LAYER met3 ;
      RECT 0.000 161.010 0.300 161.310 ;
    END
  END wd_in[41]
  PIN wd_in[42]
    DIRECTION INPUT ;
    USE SIGNAL ;
    SHAPE ABUTMENT ;
    PORT
      LAYER met3 ;
      RECT 0.000 161.690 0.300 161.990 ;
    END
  END wd_in[42]
  PIN wd_in[43]
    DIRECTION INPUT ;
    USE SIGNAL ;
    SHAPE ABUTMENT ;
    PORT
      LAYER met3 ;
      RECT 0.000 162.370 0.300 162.670 ;
    END
  END wd_in[43]
  PIN wd_in[44]
    DIRECTION INPUT ;
    USE SIGNAL ;
    SHAPE ABUTMENT ;
    PORT
      LAYER met3 ;
      RECT 0.000 163.050 0.300 163.350 ;
    END
  END wd_in[44]
  PIN wd_in[45]
    DIRECTION INPUT ;
    USE SIGNAL ;
    SHAPE ABUTMENT ;
    PORT
      LAYER met3 ;
      RECT 0.000 163.730 0.300 164.030 ;
    END
  END wd_in[45]
  PIN wd_in[46]
    DIRECTION INPUT ;
    USE SIGNAL ;
    SHAPE ABUTMENT ;
    PORT
      LAYER met3 ;
      RECT 0.000 164.410 0.300 164.710 ;
    END
  END wd_in[46]
  PIN wd_in[47]
    DIRECTION INPUT ;
    USE SIGNAL ;
    SHAPE ABUTMENT ;
    PORT
      LAYER met3 ;
      RECT 0.000 165.090 0.300 165.390 ;
    END
  END wd_in[47]
  PIN wd_in[48]
    DIRECTION INPUT ;
    USE SIGNAL ;
    SHAPE ABUTMENT ;
    PORT
      LAYER met3 ;
      RECT 0.000 165.770 0.300 166.070 ;
    END
  END wd_in[48]
  PIN wd_in[49]
    DIRECTION INPUT ;
    USE SIGNAL ;
    SHAPE ABUTMENT ;
    PORT
      LAYER met3 ;
      RECT 0.000 166.450 0.300 166.750 ;
    END
  END wd_in[49]
  PIN wd_in[50]
    DIRECTION INPUT ;
    USE SIGNAL ;
    SHAPE ABUTMENT ;
    PORT
      LAYER met3 ;
      RECT 0.000 167.130 0.300 167.430 ;
    END
  END wd_in[50]
  PIN wd_in[51]
    DIRECTION INPUT ;
    USE SIGNAL ;
    SHAPE ABUTMENT ;
    PORT
      LAYER met3 ;
      RECT 0.000 167.810 0.300 168.110 ;
    END
  END wd_in[51]
  PIN wd_in[52]
    DIRECTION INPUT ;
    USE SIGNAL ;
    SHAPE ABUTMENT ;
    PORT
      LAYER met3 ;
      RECT 0.000 168.490 0.300 168.790 ;
    END
  END wd_in[52]
  PIN wd_in[53]
    DIRECTION INPUT ;
    USE SIGNAL ;
    SHAPE ABUTMENT ;
    PORT
      LAYER met3 ;
      RECT 0.000 169.170 0.300 169.470 ;
    END
  END wd_in[53]
  PIN wd_in[54]
    DIRECTION INPUT ;
    USE SIGNAL ;
    SHAPE ABUTMENT ;
    PORT
      LAYER met3 ;
      RECT 0.000 169.850 0.300 170.150 ;
    END
  END wd_in[54]
  PIN wd_in[55]
    DIRECTION INPUT ;
    USE SIGNAL ;
    SHAPE ABUTMENT ;
    PORT
      LAYER met3 ;
      RECT 0.000 170.530 0.300 170.830 ;
    END
  END wd_in[55]
  PIN wd_in[56]
    DIRECTION INPUT ;
    USE SIGNAL ;
    SHAPE ABUTMENT ;
    PORT
      LAYER met3 ;
      RECT 0.000 171.210 0.300 171.510 ;
    END
  END wd_in[56]
  PIN wd_in[57]
    DIRECTION INPUT ;
    USE SIGNAL ;
    SHAPE ABUTMENT ;
    PORT
      LAYER met3 ;
      RECT 0.000 171.890 0.300 172.190 ;
    END
  END wd_in[57]
  PIN wd_in[58]
    DIRECTION INPUT ;
    USE SIGNAL ;
    SHAPE ABUTMENT ;
    PORT
      LAYER met3 ;
      RECT 0.000 172.570 0.300 172.870 ;
    END
  END wd_in[58]
  PIN wd_in[59]
    DIRECTION INPUT ;
    USE SIGNAL ;
    SHAPE ABUTMENT ;
    PORT
      LAYER met3 ;
      RECT 0.000 173.250 0.300 173.550 ;
    END
  END wd_in[59]
  PIN wd_in[60]
    DIRECTION INPUT ;
    USE SIGNAL ;
    SHAPE ABUTMENT ;
    PORT
      LAYER met3 ;
      RECT 0.000 173.930 0.300 174.230 ;
    END
  END wd_in[60]
  PIN wd_in[61]
    DIRECTION INPUT ;
    USE SIGNAL ;
    SHAPE ABUTMENT ;
    PORT
      LAYER met3 ;
      RECT 0.000 174.610 0.300 174.910 ;
    END
  END wd_in[61]
  PIN wd_in[62]
    DIRECTION INPUT ;
    USE SIGNAL ;
    SHAPE ABUTMENT ;
    PORT
      LAYER met3 ;
      RECT 0.000 175.290 0.300 175.590 ;
    END
  END wd_in[62]
  PIN wd_in[63]
    DIRECTION INPUT ;
    USE SIGNAL ;
    SHAPE ABUTMENT ;
    PORT
      LAYER met3 ;
      RECT 0.000 175.970 0.300 176.270 ;
    END
  END wd_in[63]
  PIN addr_in[0]
    DIRECTION INPUT ;
    USE SIGNAL ;
    SHAPE ABUTMENT ;
    PORT
      LAYER met3 ;
      RECT 0.000 196.370 0.300 196.670 ;
    END
  END addr_in[0]
  PIN addr_in[1]
    DIRECTION INPUT ;
    USE SIGNAL ;
    SHAPE ABUTMENT ;
    PORT
      LAYER met3 ;
      RECT 0.000 197.050 0.300 197.350 ;
    END
  END addr_in[1]
  PIN addr_in[2]
    DIRECTION INPUT ;
    USE SIGNAL ;
    SHAPE ABUTMENT ;
    PORT
      LAYER met3 ;
      RECT 0.000 197.730 0.300 198.030 ;
    END
  END addr_in[2]
  PIN addr_in[3]
    DIRECTION INPUT ;
    USE SIGNAL ;
    SHAPE ABUTMENT ;
    PORT
      LAYER met3 ;
      RECT 0.000 198.410 0.300 198.710 ;
    END
  END addr_in[3]
  PIN addr_in[4]
    DIRECTION INPUT ;
    USE SIGNAL ;
    SHAPE ABUTMENT ;
    PORT
      LAYER met3 ;
      RECT 0.000 199.090 0.300 199.390 ;
    END
  END addr_in[4]
  PIN addr_in[5]
    DIRECTION INPUT ;
    USE SIGNAL ;
    SHAPE ABUTMENT ;
    PORT
      LAYER met3 ;
      RECT 0.000 199.770 0.300 200.070 ;
    END
  END addr_in[5]
  PIN we_in
    DIRECTION INPUT ;
    USE SIGNAL ;
    SHAPE ABUTMENT ;
    PORT
      LAYER met3 ;
      RECT 0.000 220.170 0.300 220.470 ;
    END
  END we_in
  PIN ce_in
    DIRECTION INPUT ;
    USE SIGNAL ;
    SHAPE ABUTMENT ;
    PORT
      LAYER met3 ;
      RECT 0.000 220.850 0.300 221.150 ;
    END
  END ce_in
  PIN clk
    DIRECTION INPUT ;
    USE SIGNAL ;
    SHAPE ABUTMENT ;
    PORT
      LAYER met3 ;
      RECT 0.000 221.530 0.300 221.830 ;
    END
  END clk
  PIN VSS
    DIRECTION INOUT ;
    USE GROUND ;
    PORT
      LAYER met4 ;
      RECT 6.200 6.800 7.400 227.120 ;
      RECT 17.080 6.800 18.280 227.120 ;
      RECT 27.960 6.800 29.160 227.120 ;
      RECT 38.840 6.800 40.040 227.120 ;
      RECT 49.720 6.800 50.920 227.120 ;
      RECT 60.600 6.800 61.800 227.120 ;
      RECT 71.480 6.800 72.680 227.120 ;
      RECT 82.360 6.800 83.560 227.120 ;
      RECT 93.240 6.800 94.440 227.120 ;
      RECT 104.120 6.800 105.320 227.120 ;
      RECT 115.000 6.800 116.200 227.120 ;
      RECT 125.880 6.800 127.080 227.120 ;
      RECT 136.760 6.800 137.960 227.120 ;
      RECT 147.640 6.800 148.840 227.120 ;
      RECT 158.520 6.800 159.720 227.120 ;
      RECT 169.400 6.800 170.600 227.120 ;
      RECT 180.280 6.800 181.480 227.120 ;
    END
  END VSS
  PIN VDD
    DIRECTION INOUT ;
    USE POWER ;
    PORT
      LAYER met4 ;
      RECT 11.640 6.800 12.840 227.120 ;
      RECT 22.520 6.800 23.720 227.120 ;
      RECT 33.400 6.800 34.600 227.120 ;
      RECT 44.280 6.800 45.480 227.120 ;
      RECT 55.160 6.800 56.360 227.120 ;
      RECT 66.040 6.800 67.240 227.120 ;
      RECT 76.920 6.800 78.120 227.120 ;
      RECT 87.800 6.800 89.000 227.120 ;
      RECT 98.680 6.800 99.880 227.120 ;
      RECT 109.560 6.800 110.760 227.120 ;
      RECT 120.440 6.800 121.640 227.120 ;
      RECT 131.320 6.800 132.520 227.120 ;
      RECT 142.200 6.800 143.400 227.120 ;
      RECT 153.080 6.800 154.280 227.120 ;
      RECT 163.960 6.800 165.160 227.120 ;
      RECT 174.840 6.800 176.040 227.120 ;
    END
  END VDD
  OBS
    LAYER met1 ;
    RECT 0 0 189.980 233.920 ;
    LAYER met2 ;
    RECT 0 0 189.980 233.920 ;
    LAYER met3 ;
    RECT 0.300 0 189.980 233.920 ;
    RECT 0 0.000 0.300 6.650 ;
    RECT 0 6.950 0.300 7.330 ;
    RECT 0 7.630 0.300 8.010 ;
    RECT 0 8.310 0.300 8.690 ;
    RECT 0 8.990 0.300 9.370 ;
    RECT 0 9.670 0.300 10.050 ;
    RECT 0 10.350 0.300 10.730 ;
    RECT 0 11.030 0.300 11.410 ;
    RECT 0 11.710 0.300 12.090 ;
    RECT 0 12.390 0.300 12.770 ;
    RECT 0 13.070 0.300 13.450 ;
    RECT 0 13.750 0.300 14.130 ;
    RECT 0 14.430 0.300 14.810 ;
    RECT 0 15.110 0.300 15.490 ;
    RECT 0 15.790 0.300 16.170 ;
    RECT 0 16.470 0.300 16.850 ;
    RECT 0 17.150 0.300 17.530 ;
    RECT 0 17.830 0.300 18.210 ;
    RECT 0 18.510 0.300 18.890 ;
    RECT 0 19.190 0.300 19.570 ;
    RECT 0 19.870 0.300 20.250 ;
    RECT 0 20.550 0.300 20.930 ;
    RECT 0 21.230 0.300 21.610 ;
    RECT 0 21.910 0.300 22.290 ;
    RECT 0 22.590 0.300 22.970 ;
    RECT 0 23.270 0.300 23.650 ;
    RECT 0 23.950 0.300 24.330 ;
    RECT 0 24.630 0.300 25.010 ;
    RECT 0 25.310 0.300 25.690 ;
    RECT 0 25.990 0.300 26.370 ;
    RECT 0 26.670 0.300 27.050 ;
    RECT 0 27.350 0.300 27.730 ;
    RECT 0 28.030 0.300 28.410 ;
    RECT 0 28.710 0.300 29.090 ;
    RECT 0 29.390 0.300 29.770 ;
    RECT 0 30.070 0.300 30.450 ;
    RECT 0 30.750 0.300 31.130 ;
    RECT 0 31.430 0.300 31.810 ;
    RECT 0 32.110 0.300 32.490 ;
    RECT 0 32.790 0.300 33.170 ;
    RECT 0 33.470 0.300 33.850 ;
    RECT 0 34.150 0.300 34.530 ;
    RECT 0 34.830 0.300 35.210 ;
    RECT 0 35.510 0.300 35.890 ;
    RECT 0 36.190 0.300 36.570 ;
    RECT 0 36.870 0.300 37.250 ;
    RECT 0 37.550 0.300 37.930 ;
    RECT 0 38.230 0.300 38.610 ;
    RECT 0 38.910 0.300 39.290 ;
    RECT 0 39.590 0.300 39.970 ;
    RECT 0 40.270 0.300 40.650 ;
    RECT 0 40.950 0.300 41.330 ;
    RECT 0 41.630 0.300 42.010 ;
    RECT 0 42.310 0.300 42.690 ;
    RECT 0 42.990 0.300 43.370 ;
    RECT 0 43.670 0.300 44.050 ;
    RECT 0 44.350 0.300 44.730 ;
    RECT 0 45.030 0.300 45.410 ;
    RECT 0 45.710 0.300 46.090 ;
    RECT 0 46.390 0.300 46.770 ;
    RECT 0 47.070 0.300 47.450 ;
    RECT 0 47.750 0.300 48.130 ;
    RECT 0 48.430 0.300 48.810 ;
    RECT 0 49.110 0.300 49.490 ;
    RECT 0 49.790 0.300 69.890 ;
    RECT 0 70.190 0.300 70.570 ;
    RECT 0 70.870 0.300 71.250 ;
    RECT 0 71.550 0.300 71.930 ;
    RECT 0 72.230 0.300 72.610 ;
    RECT 0 72.910 0.300 73.290 ;
    RECT 0 73.590 0.300 73.970 ;
    RECT 0 74.270 0.300 74.650 ;
    RECT 0 74.950 0.300 75.330 ;
    RECT 0 75.630 0.300 76.010 ;
    RECT 0 76.310 0.300 76.690 ;
    RECT 0 76.990 0.300 77.370 ;
    RECT 0 77.670 0.300 78.050 ;
    RECT 0 78.350 0.300 78.730 ;
    RECT 0 79.030 0.300 79.410 ;
    RECT 0 79.710 0.300 80.090 ;
    RECT 0 80.390 0.300 80.770 ;
    RECT 0 81.070 0.300 81.450 ;
    RECT 0 81.750 0.300 82.130 ;
    RECT 0 82.430 0.300 82.810 ;
    RECT 0 83.110 0.300 83.490 ;
    RECT 0 83.790 0.300 84.170 ;
    RECT 0 84.470 0.300 84.850 ;
    RECT 0 85.150 0.300 85.530 ;
    RECT 0 85.830 0.300 86.210 ;
    RECT 0 86.510 0.300 86.890 ;
    RECT 0 87.190 0.300 87.570 ;
    RECT 0 87.870 0.300 88.250 ;
    RECT 0 88.550 0.300 88.930 ;
    RECT 0 89.230 0.300 89.610 ;
    RECT 0 89.910 0.300 90.290 ;
    RECT 0 90.590 0.300 90.970 ;
    RECT 0 91.270 0.300 91.650 ;
    RECT 0 91.950 0.300 92.330 ;
    RECT 0 92.630 0.300 93.010 ;
    RECT 0 93.310 0.300 93.690 ;
    RECT 0 93.990 0.300 94.370 ;
    RECT 0 94.670 0.300 95.050 ;
    RECT 0 95.350 0.300 95.730 ;
    RECT 0 96.030 0.300 96.410 ;
    RECT 0 96.710 0.300 97.090 ;
    RECT 0 97.390 0.300 97.770 ;
    RECT 0 98.070 0.300 98.450 ;
    RECT 0 98.750 0.300 99.130 ;
    RECT 0 99.430 0.300 99.810 ;
    RECT 0 100.110 0.300 100.490 ;
    RECT 0 100.790 0.300 101.170 ;
    RECT 0 101.470 0.300 101.850 ;
    RECT 0 102.150 0.300 102.530 ;
    RECT 0 102.830 0.300 103.210 ;
    RECT 0 103.510 0.300 103.890 ;
    RECT 0 104.190 0.300 104.570 ;
    RECT 0 104.870 0.300 105.250 ;
    RECT 0 105.550 0.300 105.930 ;
    RECT 0 106.230 0.300 106.610 ;
    RECT 0 106.910 0.300 107.290 ;
    RECT 0 107.590 0.300 107.970 ;
    RECT 0 108.270 0.300 108.650 ;
    RECT 0 108.950 0.300 109.330 ;
    RECT 0 109.630 0.300 110.010 ;
    RECT 0 110.310 0.300 110.690 ;
    RECT 0 110.990 0.300 111.370 ;
    RECT 0 111.670 0.300 112.050 ;
    RECT 0 112.350 0.300 112.730 ;
    RECT 0 113.030 0.300 133.130 ;
    RECT 0 133.430 0.300 133.810 ;
    RECT 0 134.110 0.300 134.490 ;
    RECT 0 134.790 0.300 135.170 ;
    RECT 0 135.470 0.300 135.850 ;
    RECT 0 136.150 0.300 136.530 ;
    RECT 0 136.830 0.300 137.210 ;
    RECT 0 137.510 0.300 137.890 ;
    RECT 0 138.190 0.300 138.570 ;
    RECT 0 138.870 0.300 139.250 ;
    RECT 0 139.550 0.300 139.930 ;
    RECT 0 140.230 0.300 140.610 ;
    RECT 0 140.910 0.300 141.290 ;
    RECT 0 141.590 0.300 141.970 ;
    RECT 0 142.270 0.300 142.650 ;
    RECT 0 142.950 0.300 143.330 ;
    RECT 0 143.630 0.300 144.010 ;
    RECT 0 144.310 0.300 144.690 ;
    RECT 0 144.990 0.300 145.370 ;
    RECT 0 145.670 0.300 146.050 ;
    RECT 0 146.350 0.300 146.730 ;
    RECT 0 147.030 0.300 147.410 ;
    RECT 0 147.710 0.300 148.090 ;
    RECT 0 148.390 0.300 148.770 ;
    RECT 0 149.070 0.300 149.450 ;
    RECT 0 149.750 0.300 150.130 ;
    RECT 0 150.430 0.300 150.810 ;
    RECT 0 151.110 0.300 151.490 ;
    RECT 0 151.790 0.300 152.170 ;
    RECT 0 152.470 0.300 152.850 ;
    RECT 0 153.150 0.300 153.530 ;
    RECT 0 153.830 0.300 154.210 ;
    RECT 0 154.510 0.300 154.890 ;
    RECT 0 155.190 0.300 155.570 ;
    RECT 0 155.870 0.300 156.250 ;
    RECT 0 156.550 0.300 156.930 ;
    RECT 0 157.230 0.300 157.610 ;
    RECT 0 157.910 0.300 158.290 ;
    RECT 0 158.590 0.300 158.970 ;
    RECT 0 159.270 0.300 159.650 ;
    RECT 0 159.950 0.300 160.330 ;
    RECT 0 160.630 0.300 161.010 ;
    RECT 0 161.310 0.300 161.690 ;
    RECT 0 161.990 0.300 162.370 ;
    RECT 0 162.670 0.300 163.050 ;
    RECT 0 163.350 0.300 163.730 ;
    RECT 0 164.030 0.300 164.410 ;
    RECT 0 164.710 0.300 165.090 ;
    RECT 0 165.390 0.300 165.770 ;
    RECT 0 166.070 0.300 166.450 ;
    RECT 0 166.750 0.300 167.130 ;
    RECT 0 167.430 0.300 167.810 ;
    RECT 0 168.110 0.300 168.490 ;
    RECT 0 168.790 0.300 169.170 ;
    RECT 0 169.470 0.300 169.850 ;
    RECT 0 170.150 0.300 170.530 ;
    RECT 0 170.830 0.300 171.210 ;
    RECT 0 171.510 0.300 171.890 ;
    RECT 0 172.190 0.300 172.570 ;
    RECT 0 172.870 0.300 173.250 ;
    RECT 0 173.550 0.300 173.930 ;
    RECT 0 174.230 0.300 174.610 ;
    RECT 0 174.910 0.300 175.290 ;
    RECT 0 175.590 0.300 175.970 ;
    RECT 0 176.270 0.300 196.370 ;
    RECT 0 196.670 0.300 197.050 ;
    RECT 0 197.350 0.300 197.730 ;
    RECT 0 198.030 0.300 198.410 ;
    RECT 0 198.710 0.300 199.090 ;
    RECT 0 199.390 0.300 199.770 ;
    RECT 0 200.070 0.300 220.170 ;
    RECT 0 220.470 0.300 220.850 ;
    RECT 0 221.150 0.300 221.530 ;
    RECT 0 221.830 0.300 233.920 ;
    LAYER met4 ;
    RECT 0 0 189.980 6.800 ;
    RECT 0 227.120 189.980 233.920 ;
    RECT 0.000 6.800 6.200 227.120 ;
    RECT 7.400 6.800 11.640 227.120 ;
    RECT 12.840 6.800 17.080 227.120 ;
    RECT 18.280 6.800 22.520 227.120 ;
    RECT 23.720 6.800 27.960 227.120 ;
    RECT 29.160 6.800 33.400 227.120 ;
    RECT 34.600 6.800 38.840 227.120 ;
    RECT 40.040 6.800 44.280 227.120 ;
    RECT 45.480 6.800 49.720 227.120 ;
    RECT 50.920 6.800 55.160 227.120 ;
    RECT 56.360 6.800 60.600 227.120 ;
    RECT 61.800 6.800 66.040 227.120 ;
    RECT 67.240 6.800 71.480 227.120 ;
    RECT 72.680 6.800 76.920 227.120 ;
    RECT 78.120 6.800 82.360 227.120 ;
    RECT 83.560 6.800 87.800 227.120 ;
    RECT 89.000 6.800 93.240 227.120 ;
    RECT 94.440 6.800 98.680 227.120 ;
    RECT 99.880 6.800 104.120 227.120 ;
    RECT 105.320 6.800 109.560 227.120 ;
    RECT 110.760 6.800 115.000 227.120 ;
    RECT 116.200 6.800 120.440 227.120 ;
    RECT 121.640 6.800 125.880 227.120 ;
    RECT 127.080 6.800 131.320 227.120 ;
    RECT 132.520 6.800 136.760 227.120 ;
    RECT 137.960 6.800 142.200 227.120 ;
    RECT 143.400 6.800 147.640 227.120 ;
    RECT 148.840 6.800 153.080 227.120 ;
    RECT 154.280 6.800 158.520 227.120 ;
    RECT 159.720 6.800 163.960 227.120 ;
    RECT 165.160 6.800 169.400 227.120 ;
    RECT 170.600 6.800 174.840 227.120 ;
    RECT 176.040 6.800 180.280 227.120 ;
    RECT 181.480 6.800 189.980 227.120 ;
  END
END sram_sp_64x64

END LIBRARY
